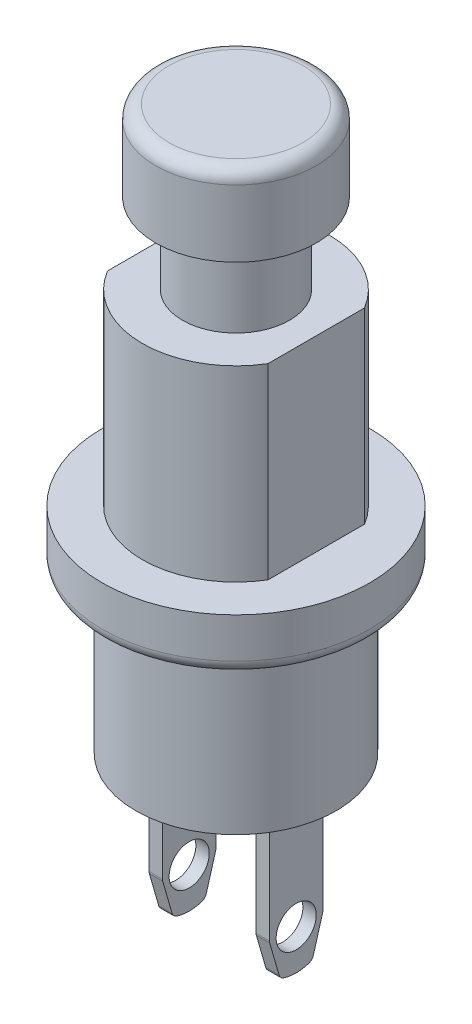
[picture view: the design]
ISO-10303-21;
HEADER;
FILE_DESCRIPTION(('STEP AP214'),'2;1');
FILE_NAME('part.step','',(''),(''),'','','');
FILE_SCHEMA(('AUTOMOTIVE_DESIGN { 1 0 10303 214 1 1 1 1 }'));
ENDSEC;
DATA;
#1=APPLICATION_CONTEXT('core data for automotive mechanical design processes');
#2=APPLICATION_PROTOCOL_DEFINITION('international standard','automotive_design',2000,#1);
#3=PRODUCT_CONTEXT('',#1,'mechanical');
#4=PRODUCT('Part','Part','',(#3));
#5=PRODUCT_RELATED_PRODUCT_CATEGORY('part','',(#4));
#6=PRODUCT_DEFINITION_FORMATION('','',#4);
#7=PRODUCT_DEFINITION_CONTEXT('part definition',#1,'design');
#8=PRODUCT_DEFINITION('design','',#6,#7);
#9=PRODUCT_DEFINITION_SHAPE('','',#8);
#10=(LENGTH_UNIT() NAMED_UNIT(*) SI_UNIT(.MILLI.,.METRE.));
#11=(NAMED_UNIT(*) PLANE_ANGLE_UNIT() SI_UNIT($,.RADIAN.));
#12=(NAMED_UNIT(*) SI_UNIT($,.STERADIAN.) SOLID_ANGLE_UNIT());
#13=UNCERTAINTY_MEASURE_WITH_UNIT(LENGTH_MEASURE(1.E-05),#10,'distance_accuracy_value','');
#14=(GEOMETRIC_REPRESENTATION_CONTEXT(3) GLOBAL_UNCERTAINTY_ASSIGNED_CONTEXT((#13)) GLOBAL_UNIT_ASSIGNED_CONTEXT((#10,
#11,#12)) REPRESENTATION_CONTEXT('',''));
#15=CARTESIAN_POINT('',(0.,0.,0.));
#16=DIRECTION('',(0.,0.,1.));
#17=DIRECTION('',(1.,0.,0.));
#18=AXIS2_PLACEMENT_3D('',#15,#16,#17);
#19=CARTESIAN_POINT('',(0.,15.,0.));
#20=DIRECTION('',(0.,1.,0.));
#21=DIRECTION('',(0.,0.,1.));
#22=AXIS2_PLACEMENT_3D('',#19,#20,#21);
#23=PLANE('',#22);
#24=CARTESIAN_POINT('',(0.,15.,0.));
#25=DIRECTION('',(0.,1.,0.));
#26=DIRECTION('',(0.,0.,1.));
#27=AXIS2_PLACEMENT_3D('',#24,#25,#26);
#28=CIRCLE('',#27,3.5);
#29=CARTESIAN_POINT('',(3.,15.,-1.802775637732));
#30=VERTEX_POINT('',#29);
#31=CARTESIAN_POINT('',(-3.,15.,-1.802775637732));
#32=VERTEX_POINT('',#31);
#33=EDGE_CURVE('E380',#30,#32,#28,.T.);
#34=ORIENTED_EDGE('',*,*,#33,.T.);
#35=DIRECTION('',(0.,0.,1.));
#36=VECTOR('',#35,1.);
#37=CARTESIAN_POINT('',(-3.,15.,1.802775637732));
#38=LINE('',#37,#36);
#39=CARTESIAN_POINT('',(-3.,15.,1.802775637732));
#40=VERTEX_POINT('',#39);
#41=EDGE_CURVE('E354',#32,#40,#38,.T.);
#42=ORIENTED_EDGE('',*,*,#41,.T.);
#43=CARTESIAN_POINT('',(0.,15.,0.));
#44=DIRECTION('',(0.,1.,0.));
#45=DIRECTION('',(0.,0.,1.));
#46=AXIS2_PLACEMENT_3D('',#43,#44,#45);
#47=CIRCLE('',#46,3.5);
#48=CARTESIAN_POINT('',(3.,15.,1.80277563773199));
#49=VERTEX_POINT('',#48);
#50=EDGE_CURVE('E383',#40,#49,#47,.T.);
#51=ORIENTED_EDGE('',*,*,#50,.T.);
#52=DIRECTION('',(0.,0.,-1.));
#53=VECTOR('',#52,1.);
#54=CARTESIAN_POINT('',(3.,15.,1.802775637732));
#55=LINE('',#54,#53);
#56=EDGE_CURVE('E385',#49,#30,#55,.T.);
#57=ORIENTED_EDGE('',*,*,#56,.T.);
#58=EDGE_LOOP('',(#34,#42,#51,#57));
#59=FACE_BOUND('',#58,.T.);
#60=CARTESIAN_POINT('',(0.,15.,0.));
#61=DIRECTION('',(0.,1.,0.));
#62=DIRECTION('',(0.,0.,1.));
#63=AXIS2_PLACEMENT_3D('',#60,#61,#62);
#64=CIRCLE('',#63,2.);
#65=CARTESIAN_POINT('',(0.,15.,2.));
#66=VERTEX_POINT('',#65);
#67=EDGE_CURVE('E1044',#66,#66,#64,.T.);
#68=ORIENTED_EDGE('',*,*,#67,.F.);
#69=EDGE_LOOP('',(#68));
#70=FACE_BOUND('',#69,.T.);
#71=ADVANCED_FACE('F136',(#59,#70),#23,.T.);
#72=CARTESIAN_POINT('',(0.,8.,0.));
#73=DIRECTION('',(0.,1.,0.));
#74=DIRECTION('',(0.,0.,1.));
#75=AXIS2_PLACEMENT_3D('',#72,#73,#74);
#76=PLANE('',#75);
#77=CARTESIAN_POINT('',(0.,8.,0.));
#78=DIRECTION('',(0.,1.,0.));
#79=DIRECTION('',(0.,0.,1.));
#80=AXIS2_PLACEMENT_3D('',#77,#78,#79);
#81=CIRCLE('',#80,5.);
#82=CARTESIAN_POINT('',(0.,8.,5.));
#83=VERTEX_POINT('',#82);
#84=EDGE_CURVE('E358',#83,#83,#81,.T.);
#85=ORIENTED_EDGE('',*,*,#84,.T.);
#86=EDGE_LOOP('',(#85));
#87=FACE_BOUND('',#86,.T.);
#88=DIRECTION('',(0.,0.,1.));
#89=VECTOR('',#88,1.);
#90=CARTESIAN_POINT('',(-3.,8.,1.802775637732));
#91=LINE('',#90,#89);
#92=CARTESIAN_POINT('',(-3.,8.,-1.802775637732));
#93=VERTEX_POINT('',#92);
#94=CARTESIAN_POINT('',(-3.,8.,1.802775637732));
#95=VERTEX_POINT('',#94);
#96=EDGE_CURVE('E352',#93,#95,#91,.T.);
#97=ORIENTED_EDGE('',*,*,#96,.F.);
#98=CARTESIAN_POINT('',(0.,8.,0.));
#99=DIRECTION('',(0.,1.,0.));
#100=DIRECTION('',(0.,0.,1.));
#101=AXIS2_PLACEMENT_3D('',#98,#99,#100);
#102=CIRCLE('',#101,3.5);
#103=CARTESIAN_POINT('',(3.,8.,-1.802775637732));
#104=VERTEX_POINT('',#103);
#105=EDGE_CURVE('E363',#104,#93,#102,.T.);
#106=ORIENTED_EDGE('',*,*,#105,.F.);
#107=DIRECTION('',(0.,0.,-1.));
#108=VECTOR('',#107,1.);
#109=CARTESIAN_POINT('',(3.,8.,1.802775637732));
#110=LINE('',#109,#108);
#111=CARTESIAN_POINT('',(3.,8.,1.80277563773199));
#112=VERTEX_POINT('',#111);
#113=EDGE_CURVE('E375',#112,#104,#110,.T.);
#114=ORIENTED_EDGE('',*,*,#113,.F.);
#115=CARTESIAN_POINT('',(0.,8.,0.));
#116=DIRECTION('',(0.,1.,0.));
#117=DIRECTION('',(0.,0.,1.));
#118=AXIS2_PLACEMENT_3D('',#115,#116,#117);
#119=CIRCLE('',#118,3.5);
#120=EDGE_CURVE('E373',#95,#112,#119,.T.);
#121=ORIENTED_EDGE('',*,*,#120,.F.);
#122=EDGE_LOOP('',(#97,#106,#114,#121));
#123=FACE_BOUND('',#122,.T.);
#124=ADVANCED_FACE('F372',(#87,#123),#76,.T.);
#125=CARTESIAN_POINT('',(1.75,-6.,1.5));
#126=DIRECTION('',(1.,0.,0.));
#127=DIRECTION('',(0.,0.,-1.));
#128=AXIS2_PLACEMENT_3D('',#125,#126,#127);
#129=PLANE('',#128);
#130=DIRECTION('',(0.,1.,0.));
#131=VECTOR('',#130,1.);
#132=CARTESIAN_POINT('',(1.75,-6.,1.));
#133=LINE('',#132,#131);
#134=CARTESIAN_POINT('',(1.75,-4.46468512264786,1.));
#135=VERTEX_POINT('',#134);
#136=CARTESIAN_POINT('',(1.75,-0.5,1.));
#137=VERTEX_POINT('',#136);
#138=EDGE_CURVE('E449',#135,#137,#133,.T.);
#139=ORIENTED_EDGE('',*,*,#138,.T.);
#140=DIRECTION('',(0.,0.,1.));
#141=VECTOR('',#140,1.);
#142=CARTESIAN_POINT('',(1.75,-0.5,1.5));
#143=LINE('',#142,#141);
#144=CARTESIAN_POINT('',(1.75,-0.5,1.5));
#145=VERTEX_POINT('',#144);
#146=EDGE_CURVE('E431',#137,#145,#143,.T.);
#147=ORIENTED_EDGE('',*,*,#146,.T.);
#148=DIRECTION('',(0.,1.,0.));
#149=VECTOR('',#148,1.);
#150=CARTESIAN_POINT('',(1.75,-6.,1.5));
#151=LINE('',#150,#149);
#152=CARTESIAN_POINT('',(1.75,0.,1.5));
#153=VERTEX_POINT('',#152);
#154=EDGE_CURVE('E568',#145,#153,#151,.T.);
#155=ORIENTED_EDGE('',*,*,#154,.T.);
#156=DIRECTION('',(0.,0.,-1.));
#157=VECTOR('',#156,1.);
#158=CARTESIAN_POINT('',(1.75,0.,1.5));
#159=LINE('',#158,#157);
#160=CARTESIAN_POINT('',(1.75,0.,-1.5));
#161=VERTEX_POINT('',#160);
#162=EDGE_CURVE('E553',#153,#161,#159,.T.);
#163=ORIENTED_EDGE('',*,*,#162,.T.);
#164=DIRECTION('',(0.,1.,0.));
#165=VECTOR('',#164,1.);
#166=CARTESIAN_POINT('',(1.75,-6.,-1.5));
#167=LINE('',#166,#165);
#168=CARTESIAN_POINT('',(1.75,-0.5,-1.5));
#169=VERTEX_POINT('',#168);
#170=EDGE_CURVE('E566',#169,#161,#167,.T.);
#171=ORIENTED_EDGE('',*,*,#170,.F.);
#172=DIRECTION('',(0.,0.,-1.));
#173=VECTOR('',#172,1.);
#174=CARTESIAN_POINT('',(1.75,-0.5,1.5));
#175=LINE('',#174,#173);
#176=CARTESIAN_POINT('',(1.75,-0.5,-1.));
#177=VERTEX_POINT('',#176);
#178=EDGE_CURVE('E530',#177,#169,#175,.T.);
#179=ORIENTED_EDGE('',*,*,#178,.F.);
#180=DIRECTION('',(0.,1.,0.));
#181=VECTOR('',#180,1.);
#182=CARTESIAN_POINT('',(1.75,-6.,-1.));
#183=LINE('',#182,#181);
#184=CARTESIAN_POINT('',(1.75,-4.46468512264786,-1.));
#185=VERTEX_POINT('',#184);
#186=EDGE_CURVE('E526',#185,#177,#183,.T.);
#187=ORIENTED_EDGE('',*,*,#186,.F.);
#188=CARTESIAN_POINT('',(1.75,-4.46468512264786,-0.75));
#189=DIRECTION('',(1.,0.,0.));
#190=DIRECTION('',(0.,0.,-1.));
#191=AXIS2_PLACEMENT_3D('',#188,#189,#190);
#192=CIRCLE('',#191,0.25);
#193=CARTESIAN_POINT('',(1.75,-4.53393308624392,-0.990218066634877));
#194=VERTEX_POINT('',#193);
#195=EDGE_CURVE('E521',#185,#194,#192,.F.);
#196=ORIENTED_EDGE('',*,*,#195,.T.);
#197=DIRECTION('',(0.,0.960872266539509,-0.276991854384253));
#198=VECTOR('',#197,1.);
#199=CARTESIAN_POINT('',(1.75,-6.55029774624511,-0.408958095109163));
#200=LINE('',#199,#198);
#201=CARTESIAN_POINT('',(1.75,-5.75410647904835,-0.638477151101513));
#202=VERTEX_POINT('',#201);
#203=EDGE_CURVE('E516',#202,#194,#200,.T.);
#204=ORIENTED_EDGE('',*,*,#203,.F.);
#205=CARTESIAN_POINT('',(1.75,-5.68485851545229,-0.398259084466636));
#206=DIRECTION('',(1.,0.,0.));
#207=DIRECTION('',(0.,0.,-1.));
#208=AXIS2_PLACEMENT_3D('',#205,#206,#207);
#209=CIRCLE('',#208,0.25);
#210=CARTESIAN_POINT('',(1.75,-5.92183021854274,-0.477910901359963));
#211=VERTEX_POINT('',#210);
#212=EDGE_CURVE('E511',#202,#211,#209,.F.);
#213=ORIENTED_EDGE('',*,*,#212,.T.);
#214=CARTESIAN_POINT('',(1.75,-4.5,0.));
#215=DIRECTION('',(1.,0.,0.));
#216=DIRECTION('',(0.,0.,-1.));
#217=AXIS2_PLACEMENT_3D('',#214,#215,#216);
#218=CIRCLE('',#217,1.5);
#219=CARTESIAN_POINT('',(1.75,-5.92183021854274,0.477910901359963));
#220=VERTEX_POINT('',#219);
#221=EDGE_CURVE('E506',#220,#211,#218,.T.);
#222=ORIENTED_EDGE('',*,*,#221,.F.);
#223=CARTESIAN_POINT('',(1.75,-5.68485851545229,0.398259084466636));
#224=DIRECTION('',(1.,0.,0.));
#225=DIRECTION('',(0.,0.,-1.));
#226=AXIS2_PLACEMENT_3D('',#223,#224,#225);
#227=CIRCLE('',#226,0.25);
#228=CARTESIAN_POINT('',(1.75,-5.75410647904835,0.638477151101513));
#229=VERTEX_POINT('',#228);
#230=EDGE_CURVE('E443',#220,#229,#227,.F.);
#231=ORIENTED_EDGE('',*,*,#230,.T.);
#232=DIRECTION('',(0.,0.960872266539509,0.276991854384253));
#233=VECTOR('',#232,1.);
#234=CARTESIAN_POINT('',(1.75,-5.75183637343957,0.639131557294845));
#235=LINE('',#234,#233);
#236=CARTESIAN_POINT('',(1.75,-4.53393308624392,0.990218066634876));
#237=VERTEX_POINT('',#236);
#238=EDGE_CURVE('E437',#229,#237,#235,.T.);
#239=ORIENTED_EDGE('',*,*,#238,.T.);
#240=CARTESIAN_POINT('',(1.75,-4.46468512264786,0.75));
#241=DIRECTION('',(1.,0.,0.));
#242=DIRECTION('',(0.,0.,-1.));
#243=AXIS2_PLACEMENT_3D('',#240,#241,#242);
#244=CIRCLE('',#243,0.25);
#245=EDGE_CURVE('E454',#135,#237,#244,.T.);
#246=ORIENTED_EDGE('',*,*,#245,.F.);
#247=EDGE_LOOP('',(#139,#147,#155,#163,#171,#179,#187,#196,#204,#213,#222,#231,#239,#246));
#248=FACE_BOUND('',#247,.T.);
#249=CARTESIAN_POINT('',(1.75,-4.5,0.));
#250=DIRECTION('',(1.,0.,0.));
#251=DIRECTION('',(0.,0.,-1.));
#252=AXIS2_PLACEMENT_3D('',#249,#250,#251);
#253=CIRCLE('',#252,0.75);
#254=CARTESIAN_POINT('',(1.75,-4.5,-0.75));
#255=VERTEX_POINT('',#254);
#256=EDGE_CURVE('E463',#255,#255,#253,.T.);
#257=ORIENTED_EDGE('',*,*,#256,.T.);
#258=EDGE_LOOP('',(#257));
#259=FACE_BOUND('',#258,.T.);
#260=ADVANCED_FACE('F631',(#248,#259),#129,.F.);
#261=CARTESIAN_POINT('',(1.75,-6.,-1.5));
#262=DIRECTION('',(0.,0.,1.));
#263=DIRECTION('',(1.,0.,0.));
#264=AXIS2_PLACEMENT_3D('',#261,#262,#263);
#265=PLANE('',#264);
#266=DIRECTION('',(-1.,0.,0.));
#267=VECTOR('',#266,1.);
#268=CARTESIAN_POINT('',(3.75,-0.5,-1.5));
#269=LINE('',#268,#267);
#270=CARTESIAN_POINT('',(2.25,-0.5,-1.5));
#271=VERTEX_POINT('',#270);
#272=EDGE_CURVE('E487',#271,#169,#269,.T.);
#273=ORIENTED_EDGE('',*,*,#272,.T.);
#274=ORIENTED_EDGE('',*,*,#170,.T.);
#275=DIRECTION('',(1.,0.,0.));
#276=VECTOR('',#275,1.);
#277=CARTESIAN_POINT('',(1.75,0.,-1.5));
#278=LINE('',#277,#276);
#279=CARTESIAN_POINT('',(2.25,0.,-1.5));
#280=VERTEX_POINT('',#279);
#281=EDGE_CURVE('E556',#161,#280,#278,.T.);
#282=ORIENTED_EDGE('',*,*,#281,.T.);
#283=DIRECTION('',(0.,1.,0.));
#284=VECTOR('',#283,1.);
#285=CARTESIAN_POINT('',(2.25,-6.,-1.5));
#286=LINE('',#285,#284);
#287=EDGE_CURVE('E564',#271,#280,#286,.T.);
#288=ORIENTED_EDGE('',*,*,#287,.F.);
#289=EDGE_LOOP('',(#273,#274,#282,#288));
#290=FACE_BOUND('',#289,.T.);
#291=ADVANCED_FACE('F742',(#290),#265,.F.);
#292=CARTESIAN_POINT('',(2.25,-6.,1.5));
#293=DIRECTION('',(-1.,0.,0.));
#294=DIRECTION('',(0.,0.,1.));
#295=AXIS2_PLACEMENT_3D('',#292,#293,#294);
#296=PLANE('',#295);
#297=CARTESIAN_POINT('',(2.25,-4.5,0.));
#298=DIRECTION('',(-1.,0.,0.));
#299=DIRECTION('',(0.,0.,1.));
#300=AXIS2_PLACEMENT_3D('',#297,#298,#299);
#301=CIRCLE('',#300,0.75);
#302=CARTESIAN_POINT('',(2.25,-4.5,0.75));
#303=VERTEX_POINT('',#302);
#304=EDGE_CURVE('E460',#303,#303,#301,.T.);
#305=ORIENTED_EDGE('',*,*,#304,.T.);
#306=EDGE_LOOP('',(#305));
#307=FACE_BOUND('',#306,.T.);
#308=DIRECTION('',(0.,1.,0.));
#309=VECTOR('',#308,1.);
#310=CARTESIAN_POINT('',(2.25,-6.,1.5));
#311=LINE('',#310,#309);
#312=CARTESIAN_POINT('',(2.25,-0.5,1.5));
#313=VERTEX_POINT('',#312);
#314=CARTESIAN_POINT('',(2.25,0.,1.5));
#315=VERTEX_POINT('',#314);
#316=EDGE_CURVE('E562',#313,#315,#311,.T.);
#317=ORIENTED_EDGE('',*,*,#316,.F.);
#318=DIRECTION('',(0.,0.,-1.));
#319=VECTOR('',#318,1.);
#320=CARTESIAN_POINT('',(2.25,-0.5,1.5));
#321=LINE('',#320,#319);
#322=CARTESIAN_POINT('',(2.25,-0.5,1.));
#323=VERTEX_POINT('',#322);
#324=EDGE_CURVE('E428',#313,#323,#321,.T.);
#325=ORIENTED_EDGE('',*,*,#324,.T.);
#326=DIRECTION('',(0.,-1.,0.));
#327=VECTOR('',#326,1.);
#328=CARTESIAN_POINT('',(2.25,-6.,1.));
#329=LINE('',#328,#327);
#330=CARTESIAN_POINT('',(2.25,-4.46468512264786,1.));
#331=VERTEX_POINT('',#330);
#332=EDGE_CURVE('E446',#323,#331,#329,.T.);
#333=ORIENTED_EDGE('',*,*,#332,.T.);
#334=CARTESIAN_POINT('',(2.25,-4.46468512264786,0.75));
#335=DIRECTION('',(-1.,0.,0.));
#336=DIRECTION('',(0.,0.,1.));
#337=AXIS2_PLACEMENT_3D('',#334,#335,#336);
#338=CIRCLE('',#337,0.25);
#339=CARTESIAN_POINT('',(2.25,-4.53393308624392,0.990218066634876));
#340=VERTEX_POINT('',#339);
#341=EDGE_CURVE('E452',#340,#331,#338,.T.);
#342=ORIENTED_EDGE('',*,*,#341,.F.);
#343=DIRECTION('',(0.,-0.960872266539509,-0.276991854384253));
#344=VECTOR('',#343,1.);
#345=CARTESIAN_POINT('',(2.25,-5.75183637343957,0.639131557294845));
#346=LINE('',#345,#344);
#347=CARTESIAN_POINT('',(2.25,-5.75410647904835,0.638477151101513));
#348=VERTEX_POINT('',#347);
#349=EDGE_CURVE('E434',#340,#348,#346,.T.);
#350=ORIENTED_EDGE('',*,*,#349,.T.);
#351=CARTESIAN_POINT('',(2.25,-5.68485851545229,0.398259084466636));
#352=DIRECTION('',(-1.,0.,0.));
#353=DIRECTION('',(0.,0.,1.));
#354=AXIS2_PLACEMENT_3D('',#351,#352,#353);
#355=CIRCLE('',#354,0.25);
#356=CARTESIAN_POINT('',(2.25,-5.92183021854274,0.477910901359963));
#357=VERTEX_POINT('',#356);
#358=EDGE_CURVE('E440',#348,#357,#355,.F.);
#359=ORIENTED_EDGE('',*,*,#358,.T.);
#360=CARTESIAN_POINT('',(2.25,-4.5,0.));
#361=DIRECTION('',(-1.,0.,0.));
#362=DIRECTION('',(0.,0.,1.));
#363=AXIS2_PLACEMENT_3D('',#360,#361,#362);
#364=CIRCLE('',#363,1.5);
#365=CARTESIAN_POINT('',(2.25,-5.92183021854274,-0.477910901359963));
#366=VERTEX_POINT('',#365);
#367=EDGE_CURVE('E504',#366,#357,#364,.T.);
#368=ORIENTED_EDGE('',*,*,#367,.F.);
#369=CARTESIAN_POINT('',(2.25,-5.68485851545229,-0.398259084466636));
#370=DIRECTION('',(-1.,0.,0.));
#371=DIRECTION('',(0.,0.,1.));
#372=AXIS2_PLACEMENT_3D('',#369,#370,#371);
#373=CIRCLE('',#372,0.25);
#374=CARTESIAN_POINT('',(2.25,-5.75410647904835,-0.638477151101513));
#375=VERTEX_POINT('',#374);
#376=EDGE_CURVE('E508',#366,#375,#373,.F.);
#377=ORIENTED_EDGE('',*,*,#376,.T.);
#378=DIRECTION('',(0.,-0.960872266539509,0.276991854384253));
#379=VECTOR('',#378,1.);
#380=CARTESIAN_POINT('',(2.25,-6.55029774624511,-0.408958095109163));
#381=LINE('',#380,#379);
#382=CARTESIAN_POINT('',(2.25,-4.53393308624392,-0.990218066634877));
#383=VERTEX_POINT('',#382);
#384=EDGE_CURVE('E514',#383,#375,#381,.T.);
#385=ORIENTED_EDGE('',*,*,#384,.F.);
#386=CARTESIAN_POINT('',(2.25,-4.46468512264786,-0.75));
#387=DIRECTION('',(-1.,0.,0.));
#388=DIRECTION('',(0.,0.,1.));
#389=AXIS2_PLACEMENT_3D('',#386,#387,#388);
#390=CIRCLE('',#389,0.25);
#391=CARTESIAN_POINT('',(2.25,-4.46468512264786,-1.));
#392=VERTEX_POINT('',#391);
#393=EDGE_CURVE('E518',#383,#392,#390,.F.);
#394=ORIENTED_EDGE('',*,*,#393,.T.);
#395=DIRECTION('',(0.,-1.,0.));
#396=VECTOR('',#395,1.);
#397=CARTESIAN_POINT('',(2.25,-6.,-1.));
#398=LINE('',#397,#396);
#399=CARTESIAN_POINT('',(2.25,-0.5,-1.));
#400=VERTEX_POINT('',#399);
#401=EDGE_CURVE('E524',#400,#392,#398,.T.);
#402=ORIENTED_EDGE('',*,*,#401,.F.);
#403=DIRECTION('',(0.,0.,1.));
#404=VECTOR('',#403,1.);
#405=CARTESIAN_POINT('',(2.25,-0.5,1.5));
#406=LINE('',#405,#404);
#407=EDGE_CURVE('E528',#271,#400,#406,.T.);
#408=ORIENTED_EDGE('',*,*,#407,.F.);
#409=ORIENTED_EDGE('',*,*,#287,.T.);
#410=DIRECTION('',(0.,0.,1.));
#411=VECTOR('',#410,1.);
#412=CARTESIAN_POINT('',(2.25,0.,1.5));
#413=LINE('',#412,#411);
#414=EDGE_CURVE('E559',#280,#315,#413,.T.);
#415=ORIENTED_EDGE('',*,*,#414,.T.);
#416=EDGE_LOOP('',(#317,#325,#333,#342,#350,#359,#368,#377,#385,#394,#402,#408,#409,#415));
#417=FACE_BOUND('',#416,.T.);
#418=ADVANCED_FACE('F734',(#307,#417),#296,.F.);
#419=CARTESIAN_POINT('',(-2.25,-6.,1.5));
#420=DIRECTION('',(1.,0.,0.));
#421=DIRECTION('',(0.,0.,-1.));
#422=AXIS2_PLACEMENT_3D('',#419,#420,#421);
#423=PLANE('',#422);
#424=DIRECTION('',(0.,-1.,0.));
#425=VECTOR('',#424,1.);
#426=CARTESIAN_POINT('',(-2.25,-10.7684253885,1.));
#427=LINE('',#426,#425);
#428=CARTESIAN_POINT('',(-2.25,-0.5,1.));
#429=VERTEX_POINT('',#428);
#430=CARTESIAN_POINT('',(-2.25,-4.46468512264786,1.));
#431=VERTEX_POINT('',#430);
#432=EDGE_CURVE('E411',#429,#431,#427,.T.);
#433=ORIENTED_EDGE('',*,*,#432,.F.);
#434=DIRECTION('',(0.,0.,-1.));
#435=VECTOR('',#434,1.);
#436=CARTESIAN_POINT('',(-2.25,-0.5,0.));
#437=LINE('',#436,#435);
#438=CARTESIAN_POINT('',(-2.25,-0.5,1.5));
#439=VERTEX_POINT('',#438);
#440=EDGE_CURVE('E415',#439,#429,#437,.T.);
#441=ORIENTED_EDGE('',*,*,#440,.F.);
#442=DIRECTION('',(0.,1.,0.));
#443=VECTOR('',#442,1.);
#444=CARTESIAN_POINT('',(-2.25,-6.,1.5));
#445=LINE('',#444,#443);
#446=CARTESIAN_POINT('',(-2.25,0.,1.5));
#447=VERTEX_POINT('',#446);
#448=EDGE_CURVE('E159',#439,#447,#445,.T.);
#449=ORIENTED_EDGE('',*,*,#448,.T.);
#450=DIRECTION('',(0.,0.,-1.));
#451=VECTOR('',#450,1.);
#452=CARTESIAN_POINT('',(-2.25,0.,1.5));
#453=LINE('',#452,#451);
#454=CARTESIAN_POINT('',(-2.25,0.,-1.5));
#455=VERTEX_POINT('',#454);
#456=EDGE_CURVE('E535',#447,#455,#453,.T.);
#457=ORIENTED_EDGE('',*,*,#456,.T.);
#458=DIRECTION('',(0.,1.,0.));
#459=VECTOR('',#458,1.);
#460=CARTESIAN_POINT('',(-2.25,-6.,-1.5));
#461=LINE('',#460,#459);
#462=CARTESIAN_POINT('',(-2.25,-0.5,-1.5));
#463=VERTEX_POINT('',#462);
#464=EDGE_CURVE('E547',#463,#455,#461,.T.);
#465=ORIENTED_EDGE('',*,*,#464,.F.);
#466=DIRECTION('',(0.,0.,1.));
#467=VECTOR('',#466,1.);
#468=CARTESIAN_POINT('',(-2.25,-0.5,0.));
#469=LINE('',#468,#467);
#470=CARTESIAN_POINT('',(-2.25,-0.5,-1.));
#471=VERTEX_POINT('',#470);
#472=EDGE_CURVE('E480',#463,#471,#469,.T.);
#473=ORIENTED_EDGE('',*,*,#472,.T.);
#474=DIRECTION('',(0.,-1.,0.));
#475=VECTOR('',#474,1.);
#476=CARTESIAN_POINT('',(-2.25,-10.7684253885,-1.));
#477=LINE('',#476,#475);
#478=CARTESIAN_POINT('',(-2.25,-4.46468512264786,-1.));
#479=VERTEX_POINT('',#478);
#480=EDGE_CURVE('E477',#471,#479,#477,.T.);
#481=ORIENTED_EDGE('',*,*,#480,.T.);
#482=CARTESIAN_POINT('',(-2.25,-4.46468512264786,-0.75));
#483=DIRECTION('',(-1.,0.,0.));
#484=DIRECTION('',(0.,0.,1.));
#485=AXIS2_PLACEMENT_3D('',#482,#483,#484);
#486=CIRCLE('',#485,0.25);
#487=CARTESIAN_POINT('',(-2.25,-4.53393308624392,-0.990218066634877));
#488=VERTEX_POINT('',#487);
#489=EDGE_CURVE('E474',#488,#479,#486,.F.);
#490=ORIENTED_EDGE('',*,*,#489,.F.);
#491=DIRECTION('',(0.,-0.960872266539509,0.276991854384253));
#492=VECTOR('',#491,1.);
#493=CARTESIAN_POINT('',(-2.25,-10.5536374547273,0.745089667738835));
#494=LINE('',#493,#492);
#495=CARTESIAN_POINT('',(-2.25,-5.75410647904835,-0.638477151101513));
#496=VERTEX_POINT('',#495);
#497=EDGE_CURVE('E471',#488,#496,#494,.T.);
#498=ORIENTED_EDGE('',*,*,#497,.T.);
#499=CARTESIAN_POINT('',(-2.25,-5.68485851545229,-0.398259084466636));
#500=DIRECTION('',(-1.,0.,0.));
#501=DIRECTION('',(0.,0.,1.));
#502=AXIS2_PLACEMENT_3D('',#499,#500,#501);
#503=CIRCLE('',#502,0.25);
#504=CARTESIAN_POINT('',(-2.25,-5.92183021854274,-0.477910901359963));
#505=VERTEX_POINT('',#504);
#506=EDGE_CURVE('E468',#505,#496,#503,.F.);
#507=ORIENTED_EDGE('',*,*,#506,.F.);
#508=CARTESIAN_POINT('',(-2.25,-4.5,0.));
#509=DIRECTION('',(-1.,0.,0.));
#510=DIRECTION('',(0.,0.,1.));
#511=AXIS2_PLACEMENT_3D('',#508,#509,#510);
#512=CIRCLE('',#511,1.5);
#513=CARTESIAN_POINT('',(-2.25,-5.92183021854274,0.477910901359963));
#514=VERTEX_POINT('',#513);
#515=EDGE_CURVE('E466',#505,#514,#512,.T.);
#516=ORIENTED_EDGE('',*,*,#515,.T.);
#517=CARTESIAN_POINT('',(-2.25,-5.68485851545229,0.398259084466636));
#518=DIRECTION('',(-1.,0.,0.));
#519=DIRECTION('',(0.,0.,1.));
#520=AXIS2_PLACEMENT_3D('',#517,#518,#519);
#521=CIRCLE('',#520,0.25);
#522=CARTESIAN_POINT('',(-2.25,-5.75410647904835,0.638477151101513));
#523=VERTEX_POINT('',#522);
#524=EDGE_CURVE('E418',#523,#514,#521,.F.);
#525=ORIENTED_EDGE('',*,*,#524,.F.);
#526=DIRECTION('',(0.,-0.960872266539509,-0.276991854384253));
#527=VECTOR('',#526,1.);
#528=CARTESIAN_POINT('',(-2.25,-10.5536374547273,-0.745089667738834));
#529=LINE('',#528,#527);
#530=CARTESIAN_POINT('',(-2.25,-4.53393308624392,0.990218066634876));
#531=VERTEX_POINT('',#530);
#532=EDGE_CURVE('E421',#531,#523,#529,.T.);
#533=ORIENTED_EDGE('',*,*,#532,.F.);
#534=CARTESIAN_POINT('',(-2.25,-4.46468512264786,0.75));
#535=DIRECTION('',(-1.,0.,0.));
#536=DIRECTION('',(0.,0.,1.));
#537=AXIS2_PLACEMENT_3D('',#534,#535,#536);
#538=CIRCLE('',#537,0.25);
#539=EDGE_CURVE('E392',#531,#431,#538,.T.);
#540=ORIENTED_EDGE('',*,*,#539,.T.);
#541=EDGE_LOOP('',(#433,#441,#449,#457,#465,#473,#481,#490,#498,#507,#516,#525,#533,#540));
#542=FACE_BOUND('',#541,.T.);
#543=CARTESIAN_POINT('',(-2.25,-4.5,0.));
#544=DIRECTION('',(-1.,0.,0.));
#545=DIRECTION('',(0.,0.,1.));
#546=AXIS2_PLACEMENT_3D('',#543,#544,#545);
#547=CIRCLE('',#546,0.75);
#548=CARTESIAN_POINT('',(-2.25,-4.5,0.75));
#549=VERTEX_POINT('',#548);
#550=EDGE_CURVE('E456',#549,#549,#547,.T.);
#551=ORIENTED_EDGE('',*,*,#550,.F.);
#552=EDGE_LOOP('',(#551));
#553=FACE_BOUND('',#552,.T.);
#554=ADVANCED_FACE('F730',(#542,#553),#423,.F.);
#555=CARTESIAN_POINT('',(-2.25,-6.,-1.5));
#556=DIRECTION('',(0.,0.,1.));
#557=DIRECTION('',(1.,0.,0.));
#558=AXIS2_PLACEMENT_3D('',#555,#556,#557);
#559=PLANE('',#558);
#560=CARTESIAN_POINT('',(-1.75,-0.5,-1.5));
#561=VERTEX_POINT('',#560);
#562=EDGE_CURVE('E484',#561,#463,#269,.T.);
#563=ORIENTED_EDGE('',*,*,#562,.T.);
#564=ORIENTED_EDGE('',*,*,#464,.T.);
#565=DIRECTION('',(1.,0.,0.));
#566=VECTOR('',#565,1.);
#567=CARTESIAN_POINT('',(-2.25,0.,-1.5));
#568=LINE('',#567,#566);
#569=CARTESIAN_POINT('',(-1.75,0.,-1.5));
#570=VERTEX_POINT('',#569);
#571=EDGE_CURVE('E537',#455,#570,#568,.T.);
#572=ORIENTED_EDGE('',*,*,#571,.T.);
#573=DIRECTION('',(0.,1.,0.));
#574=VECTOR('',#573,1.);
#575=CARTESIAN_POINT('',(-1.75,-6.,-1.5));
#576=LINE('',#575,#574);
#577=EDGE_CURVE('E545',#561,#570,#576,.T.);
#578=ORIENTED_EDGE('',*,*,#577,.F.);
#579=EDGE_LOOP('',(#563,#564,#572,#578));
#580=FACE_BOUND('',#579,.T.);
#581=ADVANCED_FACE('F726',(#580),#559,.F.);
#582=CARTESIAN_POINT('',(-1.75,-6.,1.5));
#583=DIRECTION('',(-1.,0.,0.));
#584=DIRECTION('',(0.,0.,1.));
#585=AXIS2_PLACEMENT_3D('',#582,#583,#584);
#586=PLANE('',#585);
#587=CARTESIAN_POINT('',(-1.75,-4.5,0.));
#588=DIRECTION('',(-1.,0.,0.));
#589=DIRECTION('',(0.,0.,1.));
#590=AXIS2_PLACEMENT_3D('',#587,#588,#589);
#591=CIRCLE('',#590,0.75);
#592=CARTESIAN_POINT('',(-1.75,-4.5,0.75));
#593=VERTEX_POINT('',#592);
#594=EDGE_CURVE('E459',#593,#593,#591,.T.);
#595=ORIENTED_EDGE('',*,*,#594,.T.);
#596=EDGE_LOOP('',(#595));
#597=FACE_BOUND('',#596,.T.);
#598=DIRECTION('',(0.,1.,0.));
#599=VECTOR('',#598,1.);
#600=CARTESIAN_POINT('',(-1.75,-6.,1.5));
#601=LINE('',#600,#599);
#602=CARTESIAN_POINT('',(-1.75,-0.5,1.5));
#603=VERTEX_POINT('',#602);
#604=CARTESIAN_POINT('',(-1.75,0.,1.5));
#605=VERTEX_POINT('',#604);
#606=EDGE_CURVE('E543',#603,#605,#601,.T.);
#607=ORIENTED_EDGE('',*,*,#606,.F.);
#608=DIRECTION('',(0.,0.,-1.));
#609=VECTOR('',#608,1.);
#610=CARTESIAN_POINT('',(-1.75,-0.5,1.5));
#611=LINE('',#610,#609);
#612=CARTESIAN_POINT('',(-1.75,-0.5,1.));
#613=VERTEX_POINT('',#612);
#614=EDGE_CURVE('E414',#603,#613,#611,.T.);
#615=ORIENTED_EDGE('',*,*,#614,.T.);
#616=DIRECTION('',(0.,-1.,0.));
#617=VECTOR('',#616,1.);
#618=CARTESIAN_POINT('',(-1.75,-6.,1.));
#619=LINE('',#618,#617);
#620=CARTESIAN_POINT('',(-1.75,-4.46468512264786,1.));
#621=VERTEX_POINT('',#620);
#622=EDGE_CURVE('E601',#613,#621,#619,.T.);
#623=ORIENTED_EDGE('',*,*,#622,.T.);
#624=CARTESIAN_POINT('',(-1.75,-4.46468512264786,0.75));
#625=DIRECTION('',(-1.,0.,0.));
#626=DIRECTION('',(0.,0.,1.));
#627=AXIS2_PLACEMENT_3D('',#624,#625,#626);
#628=CIRCLE('',#627,0.25);
#629=CARTESIAN_POINT('',(-1.75,-4.53393308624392,0.990218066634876));
#630=VERTEX_POINT('',#629);
#631=EDGE_CURVE('E599',#630,#621,#628,.T.);
#632=ORIENTED_EDGE('',*,*,#631,.F.);
#633=DIRECTION('',(0.,-0.960872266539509,-0.276991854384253));
#634=VECTOR('',#633,1.);
#635=CARTESIAN_POINT('',(-1.75,-5.75183637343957,0.639131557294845));
#636=LINE('',#635,#634);
#637=CARTESIAN_POINT('',(-1.75,-5.75410647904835,0.638477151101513));
#638=VERTEX_POINT('',#637);
#639=EDGE_CURVE('E593',#630,#638,#636,.T.);
#640=ORIENTED_EDGE('',*,*,#639,.T.);
#641=CARTESIAN_POINT('',(-1.75,-5.68485851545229,0.398259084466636));
#642=DIRECTION('',(-1.,0.,0.));
#643=DIRECTION('',(0.,0.,1.));
#644=AXIS2_PLACEMENT_3D('',#641,#642,#643);
#645=CIRCLE('',#644,0.25);
#646=CARTESIAN_POINT('',(-1.75,-5.92183021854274,0.477910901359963));
#647=VERTEX_POINT('',#646);
#648=EDGE_CURVE('E596',#638,#647,#645,.F.);
#649=ORIENTED_EDGE('',*,*,#648,.T.);
#650=CARTESIAN_POINT('',(-1.75,-4.5,0.));
#651=DIRECTION('',(-1.,0.,0.));
#652=DIRECTION('',(0.,0.,1.));
#653=AXIS2_PLACEMENT_3D('',#650,#651,#652);
#654=CIRCLE('',#653,1.5);
#655=CARTESIAN_POINT('',(-1.75,-5.92183021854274,-0.477910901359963));
#656=VERTEX_POINT('',#655);
#657=EDGE_CURVE('E502',#656,#647,#654,.T.);
#658=ORIENTED_EDGE('',*,*,#657,.F.);
#659=CARTESIAN_POINT('',(-1.75,-5.68485851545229,-0.398259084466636));
#660=DIRECTION('',(-1.,0.,0.));
#661=DIRECTION('',(0.,0.,1.));
#662=AXIS2_PLACEMENT_3D('',#659,#660,#661);
#663=CIRCLE('',#662,0.25);
#664=CARTESIAN_POINT('',(-1.75,-5.75410647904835,-0.638477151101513));
#665=VERTEX_POINT('',#664);
#666=EDGE_CURVE('E576',#656,#665,#663,.F.);
#667=ORIENTED_EDGE('',*,*,#666,.T.);
#668=DIRECTION('',(0.,-0.960872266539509,0.276991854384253));
#669=VECTOR('',#668,1.);
#670=CARTESIAN_POINT('',(-1.75,-6.55029774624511,-0.408958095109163));
#671=LINE('',#670,#669);
#672=CARTESIAN_POINT('',(-1.75,-4.53393308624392,-0.990218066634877));
#673=VERTEX_POINT('',#672);
#674=EDGE_CURVE('E579',#673,#665,#671,.T.);
#675=ORIENTED_EDGE('',*,*,#674,.F.);
#676=CARTESIAN_POINT('',(-1.75,-4.46468512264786,-0.75));
#677=DIRECTION('',(-1.,0.,0.));
#678=DIRECTION('',(0.,0.,1.));
#679=AXIS2_PLACEMENT_3D('',#676,#677,#678);
#680=CIRCLE('',#679,0.25);
#681=CARTESIAN_POINT('',(-1.75,-4.46468512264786,-1.));
#682=VERTEX_POINT('',#681);
#683=EDGE_CURVE('E581',#673,#682,#680,.F.);
#684=ORIENTED_EDGE('',*,*,#683,.T.);
#685=DIRECTION('',(0.,-1.,0.));
#686=VECTOR('',#685,1.);
#687=CARTESIAN_POINT('',(-1.75,-6.,-1.));
#688=LINE('',#687,#686);
#689=CARTESIAN_POINT('',(-1.75,-0.5,-1.));
#690=VERTEX_POINT('',#689);
#691=EDGE_CURVE('E584',#690,#682,#688,.T.);
#692=ORIENTED_EDGE('',*,*,#691,.F.);
#693=DIRECTION('',(0.,0.,1.));
#694=VECTOR('',#693,1.);
#695=CARTESIAN_POINT('',(-1.75,-0.5,1.5));
#696=LINE('',#695,#694);
#697=EDGE_CURVE('E586',#561,#690,#696,.T.);
#698=ORIENTED_EDGE('',*,*,#697,.F.);
#699=ORIENTED_EDGE('',*,*,#577,.T.);
#700=DIRECTION('',(0.,0.,1.));
#701=VECTOR('',#700,1.);
#702=CARTESIAN_POINT('',(-1.75,0.,1.5));
#703=LINE('',#702,#701);
#704=EDGE_CURVE('E540',#570,#605,#703,.T.);
#705=ORIENTED_EDGE('',*,*,#704,.T.);
#706=EDGE_LOOP('',(#607,#615,#623,#632,#640,#649,#658,#667,#675,#684,#692,#698,#699,#705));
#707=FACE_BOUND('',#706,.T.);
#708=ADVANCED_FACE('F722',(#597,#707),#586,.F.);
#709=CARTESIAN_POINT('',(0.,0.,0.));
#710=DIRECTION('',(0.,1.,0.));
#711=DIRECTION('',(0.,0.,1.));
#712=AXIS2_PLACEMENT_3D('',#709,#710,#711);
#713=PLANE('',#712);
#714=DIRECTION('',(-1.,0.,0.));
#715=VECTOR('',#714,1.);
#716=CARTESIAN_POINT('',(1.75,0.,1.5));
#717=LINE('',#716,#715);
#718=EDGE_CURVE('E550',#315,#153,#717,.T.);
#719=ORIENTED_EDGE('',*,*,#718,.F.);
#720=ORIENTED_EDGE('',*,*,#414,.F.);
#721=ORIENTED_EDGE('',*,*,#281,.F.);
#722=ORIENTED_EDGE('',*,*,#162,.F.);
#723=EDGE_LOOP('',(#719,#720,#721,#722));
#724=FACE_BOUND('',#723,.T.);
#725=CARTESIAN_POINT('',(0.,0.,0.));
#726=DIRECTION('',(0.,1.,0.));
#727=DIRECTION('',(0.,0.,1.));
#728=AXIS2_PLACEMENT_3D('',#725,#726,#727);
#729=CIRCLE('',#728,3.75);
#730=CARTESIAN_POINT('',(0.,0.,3.75));
#731=VERTEX_POINT('',#730);
#732=EDGE_CURVE('E570',#731,#731,#729,.T.);
#733=ORIENTED_EDGE('',*,*,#732,.F.);
#734=EDGE_LOOP('',(#733));
#735=FACE_BOUND('',#734,.T.);
#736=DIRECTION('',(-1.,0.,0.));
#737=VECTOR('',#736,1.);
#738=CARTESIAN_POINT('',(-2.25,0.,1.5));
#739=LINE('',#738,#737);
#740=EDGE_CURVE('E532',#605,#447,#739,.T.);
#741=ORIENTED_EDGE('',*,*,#740,.F.);
#742=ORIENTED_EDGE('',*,*,#704,.F.);
#743=ORIENTED_EDGE('',*,*,#571,.F.);
#744=ORIENTED_EDGE('',*,*,#456,.F.);
#745=EDGE_LOOP('',(#741,#742,#743,#744));
#746=FACE_BOUND('',#745,.T.);
#747=ADVANCED_FACE('F725',(#724,#735,#746),#713,.F.);
#748=CARTESIAN_POINT('',(0.,6.,0.));
#749=DIRECTION('',(0.,-1.,0.));
#750=DIRECTION('',(0.,0.,-1.));
#751=AXIS2_PLACEMENT_3D('',#748,#749,#750);
#752=CYLINDRICAL_SURFACE('',#751,3.75);
#753=CARTESIAN_POINT('',(0.,6.,0.));
#754=DIRECTION('',(0.,1.,0.));
#755=DIRECTION('',(0.,0.,1.));
#756=AXIS2_PLACEMENT_3D('',#753,#754,#755);
#757=CIRCLE('',#756,3.75);
#758=CARTESIAN_POINT('',(0.,6.,3.75));
#759=VERTEX_POINT('',#758);
#760=EDGE_CURVE('E573',#759,#759,#757,.T.);
#761=ORIENTED_EDGE('',*,*,#760,.F.);
#762=EDGE_LOOP('',(#761));
#763=FACE_BOUND('',#762,.T.);
#764=ORIENTED_EDGE('',*,*,#732,.T.);
#765=EDGE_LOOP('',(#764));
#766=FACE_BOUND('',#765,.T.);
#767=ADVANCED_FACE('F138',(#763,#766),#752,.T.);
#768=CARTESIAN_POINT('',(1.75,-6.,1.5));
#769=DIRECTION('',(0.,0.,-1.));
#770=DIRECTION('',(-1.,0.,0.));
#771=AXIS2_PLACEMENT_3D('',#768,#769,#770);
#772=PLANE('',#771);
#773=ORIENTED_EDGE('',*,*,#154,.F.);
#774=DIRECTION('',(-1.,0.,0.));
#775=VECTOR('',#774,1.);
#776=CARTESIAN_POINT('',(3.75,-0.5,1.5));
#777=LINE('',#776,#775);
#778=EDGE_CURVE('E403',#313,#145,#777,.T.);
#779=ORIENTED_EDGE('',*,*,#778,.F.);
#780=ORIENTED_EDGE('',*,*,#316,.T.);
#781=ORIENTED_EDGE('',*,*,#718,.T.);
#782=EDGE_LOOP('',(#773,#779,#780,#781));
#783=FACE_BOUND('',#782,.T.);
#784=ADVANCED_FACE('F738',(#783),#772,.F.);
#785=CARTESIAN_POINT('',(-2.25,-6.,1.5));
#786=DIRECTION('',(0.,0.,-1.));
#787=DIRECTION('',(-1.,0.,0.));
#788=AXIS2_PLACEMENT_3D('',#785,#786,#787);
#789=PLANE('',#788);
#790=ORIENTED_EDGE('',*,*,#448,.F.);
#791=DIRECTION('',(1.,0.,0.));
#792=VECTOR('',#791,1.);
#793=CARTESIAN_POINT('',(-2.25,-0.5,1.5));
#794=LINE('',#793,#792);
#795=EDGE_CURVE('E588',#439,#603,#794,.T.);
#796=ORIENTED_EDGE('',*,*,#795,.T.);
#797=ORIENTED_EDGE('',*,*,#606,.T.);
#798=ORIENTED_EDGE('',*,*,#740,.T.);
#799=EDGE_LOOP('',(#790,#796,#797,#798));
#800=FACE_BOUND('',#799,.T.);
#801=ADVANCED_FACE('F735',(#800),#789,.F.);
#802=CARTESIAN_POINT('',(3.75,-4.5,0.));
#803=DIRECTION('',(-1.,0.,0.));
#804=DIRECTION('',(0.,0.,1.));
#805=AXIS2_PLACEMENT_3D('',#802,#803,#804);
#806=CYLINDRICAL_SURFACE('',#805,1.5);
#807=ORIENTED_EDGE('',*,*,#657,.T.);
#808=DIRECTION('',(-1.,0.,0.));
#809=VECTOR('',#808,1.);
#810=CARTESIAN_POINT('',(3.75,-5.92183021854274,0.477910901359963));
#811=LINE('',#810,#809);
#812=EDGE_CURVE('E400',#647,#514,#811,.T.);
#813=ORIENTED_EDGE('',*,*,#812,.T.);
#814=ORIENTED_EDGE('',*,*,#515,.F.);
#815=DIRECTION('',(-1.,0.,0.));
#816=VECTOR('',#815,1.);
#817=CARTESIAN_POINT('',(3.75,-5.92183021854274,-0.477910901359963));
#818=LINE('',#817,#816);
#819=EDGE_CURVE('E483',#656,#505,#818,.T.);
#820=ORIENTED_EDGE('',*,*,#819,.F.);
#821=EDGE_LOOP('',(#807,#813,#814,#820));
#822=FACE_BOUND('',#821,.T.);
#823=ADVANCED_FACE('F721',(#822),#806,.T.);
#824=CARTESIAN_POINT('',(3.75,-5.68485851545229,-0.398259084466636));
#825=DIRECTION('',(-1.,0.,0.));
#826=DIRECTION('',(0.,0.,1.));
#827=AXIS2_PLACEMENT_3D('',#824,#825,#826);
#828=CYLINDRICAL_SURFACE('',#827,0.25);
#829=ORIENTED_EDGE('',*,*,#819,.T.);
#830=ORIENTED_EDGE('',*,*,#506,.T.);
#831=DIRECTION('',(-1.,0.,0.));
#832=VECTOR('',#831,1.);
#833=CARTESIAN_POINT('',(3.75,-5.75410647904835,-0.638477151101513));
#834=LINE('',#833,#832);
#835=EDGE_CURVE('E498',#665,#496,#834,.T.);
#836=ORIENTED_EDGE('',*,*,#835,.F.);
#837=ORIENTED_EDGE('',*,*,#666,.F.);
#838=EDGE_LOOP('',(#829,#830,#836,#837));
#839=FACE_BOUND('',#838,.T.);
#840=ADVANCED_FACE('F717',(#839),#828,.T.);
#841=CARTESIAN_POINT('',(3.75,-10.5536374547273,0.745089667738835));
#842=DIRECTION('',(0.,-0.276991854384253,-0.960872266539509));
#843=DIRECTION('',(0.,0.960872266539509,-0.276991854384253));
#844=AXIS2_PLACEMENT_3D('',#841,#842,#843);
#845=PLANE('',#844);
#846=ORIENTED_EDGE('',*,*,#674,.T.);
#847=ORIENTED_EDGE('',*,*,#835,.T.);
#848=ORIENTED_EDGE('',*,*,#497,.F.);
#849=DIRECTION('',(-1.,0.,0.));
#850=VECTOR('',#849,1.);
#851=CARTESIAN_POINT('',(3.75,-4.53393308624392,-0.990218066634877));
#852=LINE('',#851,#850);
#853=EDGE_CURVE('E495',#673,#488,#852,.T.);
#854=ORIENTED_EDGE('',*,*,#853,.F.);
#855=EDGE_LOOP('',(#846,#847,#848,#854));
#856=FACE_BOUND('',#855,.T.);
#857=ADVANCED_FACE('F712',(#856),#845,.T.);
#858=CARTESIAN_POINT('',(3.75,-4.46468512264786,-0.75));
#859=DIRECTION('',(-1.,0.,0.));
#860=DIRECTION('',(0.,0.,1.));
#861=AXIS2_PLACEMENT_3D('',#858,#859,#860);
#862=CYLINDRICAL_SURFACE('',#861,0.25);
#863=ORIENTED_EDGE('',*,*,#853,.T.);
#864=ORIENTED_EDGE('',*,*,#489,.T.);
#865=DIRECTION('',(-1.,0.,0.));
#866=VECTOR('',#865,1.);
#867=CARTESIAN_POINT('',(3.75,-4.46468512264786,-1.));
#868=LINE('',#867,#866);
#869=EDGE_CURVE('E492',#682,#479,#868,.T.);
#870=ORIENTED_EDGE('',*,*,#869,.F.);
#871=ORIENTED_EDGE('',*,*,#683,.F.);
#872=EDGE_LOOP('',(#863,#864,#870,#871));
#873=FACE_BOUND('',#872,.T.);
#874=ADVANCED_FACE('F707',(#873),#862,.T.);
#875=CARTESIAN_POINT('',(3.75,-10.7684253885,-1.));
#876=DIRECTION('',(0.,0.,-1.));
#877=DIRECTION('',(-1.,0.,0.));
#878=AXIS2_PLACEMENT_3D('',#875,#876,#877);
#879=PLANE('',#878);
#880=ORIENTED_EDGE('',*,*,#691,.T.);
#881=ORIENTED_EDGE('',*,*,#869,.T.);
#882=ORIENTED_EDGE('',*,*,#480,.F.);
#883=DIRECTION('',(-1.,0.,0.));
#884=VECTOR('',#883,1.);
#885=CARTESIAN_POINT('',(3.75,-0.5,-1.));
#886=LINE('',#885,#884);
#887=EDGE_CURVE('E489',#690,#471,#886,.T.);
#888=ORIENTED_EDGE('',*,*,#887,.F.);
#889=EDGE_LOOP('',(#880,#881,#882,#888));
#890=FACE_BOUND('',#889,.T.);
#891=ADVANCED_FACE('F702',(#890),#879,.T.);
#892=CARTESIAN_POINT('',(3.75,-0.5,0.));
#893=DIRECTION('',(0.,-1.,0.));
#894=DIRECTION('',(0.,0.,-1.));
#895=AXIS2_PLACEMENT_3D('',#892,#893,#894);
#896=PLANE('',#895);
#897=ORIENTED_EDGE('',*,*,#697,.T.);
#898=ORIENTED_EDGE('',*,*,#887,.T.);
#899=ORIENTED_EDGE('',*,*,#472,.F.);
#900=ORIENTED_EDGE('',*,*,#562,.F.);
#901=EDGE_LOOP('',(#897,#898,#899,#900));
#902=FACE_BOUND('',#901,.T.);
#903=ADVANCED_FACE('F696',(#902),#896,.T.);
#904=ORIENTED_EDGE('',*,*,#178,.T.);
#905=ORIENTED_EDGE('',*,*,#272,.F.);
#906=ORIENTED_EDGE('',*,*,#407,.T.);
#907=EDGE_CURVE('E488',#400,#177,#886,.T.);
#908=ORIENTED_EDGE('',*,*,#907,.T.);
#909=EDGE_LOOP('',(#904,#905,#906,#908));
#910=FACE_BOUND('',#909,.T.);
#911=ADVANCED_FACE('F692',(#910),#896,.T.);
#912=ORIENTED_EDGE('',*,*,#186,.T.);
#913=ORIENTED_EDGE('',*,*,#907,.F.);
#914=ORIENTED_EDGE('',*,*,#401,.T.);
#915=EDGE_CURVE('E491',#392,#185,#868,.T.);
#916=ORIENTED_EDGE('',*,*,#915,.T.);
#917=EDGE_LOOP('',(#912,#913,#914,#916));
#918=FACE_BOUND('',#917,.T.);
#919=ADVANCED_FACE('F695',(#918),#879,.T.);
#920=ORIENTED_EDGE('',*,*,#915,.F.);
#921=ORIENTED_EDGE('',*,*,#393,.F.);
#922=EDGE_CURVE('E494',#383,#194,#852,.T.);
#923=ORIENTED_EDGE('',*,*,#922,.T.);
#924=ORIENTED_EDGE('',*,*,#195,.F.);
#925=EDGE_LOOP('',(#920,#921,#923,#924));
#926=FACE_BOUND('',#925,.T.);
#927=ADVANCED_FACE('F700',(#926),#862,.T.);
#928=ORIENTED_EDGE('',*,*,#203,.T.);
#929=ORIENTED_EDGE('',*,*,#922,.F.);
#930=ORIENTED_EDGE('',*,*,#384,.T.);
#931=EDGE_CURVE('E497',#375,#202,#834,.T.);
#932=ORIENTED_EDGE('',*,*,#931,.T.);
#933=EDGE_LOOP('',(#928,#929,#930,#932));
#934=FACE_BOUND('',#933,.T.);
#935=ADVANCED_FACE('F705',(#934),#845,.T.);
#936=ORIENTED_EDGE('',*,*,#931,.F.);
#937=ORIENTED_EDGE('',*,*,#376,.F.);
#938=EDGE_CURVE('E500',#366,#211,#818,.T.);
#939=ORIENTED_EDGE('',*,*,#938,.T.);
#940=ORIENTED_EDGE('',*,*,#212,.F.);
#941=EDGE_LOOP('',(#936,#937,#939,#940));
#942=FACE_BOUND('',#941,.T.);
#943=ADVANCED_FACE('F710',(#942),#828,.T.);
#944=ORIENTED_EDGE('',*,*,#221,.T.);
#945=ORIENTED_EDGE('',*,*,#938,.F.);
#946=ORIENTED_EDGE('',*,*,#367,.T.);
#947=EDGE_CURVE('E399',#357,#220,#811,.T.);
#948=ORIENTED_EDGE('',*,*,#947,.T.);
#949=EDGE_LOOP('',(#944,#945,#946,#948));
#950=FACE_BOUND('',#949,.T.);
#951=ADVANCED_FACE('F715',(#950),#806,.T.);
#952=CARTESIAN_POINT('',(3.75,-4.5,0.));
#953=DIRECTION('',(-1.,0.,0.));
#954=DIRECTION('',(0.,0.,1.));
#955=AXIS2_PLACEMENT_3D('',#952,#953,#954);
#956=CYLINDRICAL_SURFACE('',#955,0.75);
#957=ORIENTED_EDGE('',*,*,#550,.T.);
#958=EDGE_LOOP('',(#957));
#959=FACE_BOUND('',#958,.T.);
#960=ORIENTED_EDGE('',*,*,#594,.F.);
#961=EDGE_LOOP('',(#960));
#962=FACE_BOUND('',#961,.T.);
#963=ADVANCED_FACE('F690',(#959,#962),#956,.F.);
#964=ORIENTED_EDGE('',*,*,#304,.F.);
#965=EDGE_LOOP('',(#964));
#966=FACE_BOUND('',#965,.T.);
#967=ORIENTED_EDGE('',*,*,#256,.F.);
#968=EDGE_LOOP('',(#967));
#969=FACE_BOUND('',#968,.T.);
#970=ADVANCED_FACE('F673',(#966,#969),#956,.F.);
#971=CARTESIAN_POINT('',(3.75,-10.5536374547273,-0.745089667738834));
#972=DIRECTION('',(0.,0.276991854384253,-0.960872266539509));
#973=DIRECTION('',(0.,0.960872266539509,0.276991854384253));
#974=AXIS2_PLACEMENT_3D('',#971,#972,#973);
#975=PLANE('',#974);
#976=DIRECTION('',(-1.,0.,0.));
#977=VECTOR('',#976,1.);
#978=CARTESIAN_POINT('',(3.75,-5.75410647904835,0.638477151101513));
#979=LINE('',#978,#977);
#980=EDGE_CURVE('E398',#348,#229,#979,.T.);
#981=ORIENTED_EDGE('',*,*,#980,.F.);
#982=ORIENTED_EDGE('',*,*,#349,.F.);
#983=DIRECTION('',(-1.,0.,0.));
#984=VECTOR('',#983,1.);
#985=CARTESIAN_POINT('',(3.75,-4.53393308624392,0.990218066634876));
#986=LINE('',#985,#984);
#987=EDGE_CURVE('E395',#340,#237,#986,.T.);
#988=ORIENTED_EDGE('',*,*,#987,.T.);
#989=ORIENTED_EDGE('',*,*,#238,.F.);
#990=EDGE_LOOP('',(#981,#982,#988,#989));
#991=FACE_BOUND('',#990,.T.);
#992=ADVANCED_FACE('F669',(#991),#975,.F.);
#993=CARTESIAN_POINT('',(3.75,-5.68485851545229,0.398259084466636));
#994=DIRECTION('',(-1.,0.,0.));
#995=DIRECTION('',(0.,0.,1.));
#996=AXIS2_PLACEMENT_3D('',#993,#994,#995);
#997=CYLINDRICAL_SURFACE('',#996,0.25);
#998=ORIENTED_EDGE('',*,*,#947,.F.);
#999=ORIENTED_EDGE('',*,*,#358,.F.);
#1000=ORIENTED_EDGE('',*,*,#980,.T.);
#1001=ORIENTED_EDGE('',*,*,#230,.F.);
#1002=EDGE_LOOP('',(#998,#999,#1000,#1001));
#1003=FACE_BOUND('',#1002,.T.);
#1004=ADVANCED_FACE('F672',(#1003),#997,.T.);
#1005=CARTESIAN_POINT('',(3.75,-0.5,0.));
#1006=DIRECTION('',(0.,1.,0.));
#1007=DIRECTION('',(0.,0.,1.));
#1008=AXIS2_PLACEMENT_3D('',#1005,#1006,#1007);
#1009=PLANE('',#1008);
#1010=DIRECTION('',(-1.,0.,0.));
#1011=VECTOR('',#1010,1.);
#1012=CARTESIAN_POINT('',(3.75,-0.5,1.));
#1013=LINE('',#1012,#1011);
#1014=EDGE_CURVE('E405',#323,#137,#1013,.T.);
#1015=ORIENTED_EDGE('',*,*,#1014,.F.);
#1016=ORIENTED_EDGE('',*,*,#324,.F.);
#1017=ORIENTED_EDGE('',*,*,#778,.T.);
#1018=ORIENTED_EDGE('',*,*,#146,.F.);
#1019=EDGE_LOOP('',(#1015,#1016,#1017,#1018));
#1020=FACE_BOUND('',#1019,.T.);
#1021=ADVANCED_FACE('F678',(#1020),#1009,.F.);
#1022=CARTESIAN_POINT('',(3.75,-10.7684253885,1.));
#1023=DIRECTION('',(0.,0.,-1.));
#1024=DIRECTION('',(-1.,0.,0.));
#1025=AXIS2_PLACEMENT_3D('',#1022,#1023,#1024);
#1026=PLANE('',#1025);
#1027=DIRECTION('',(-1.,0.,0.));
#1028=VECTOR('',#1027,1.);
#1029=CARTESIAN_POINT('',(3.75,-4.46468512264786,1.));
#1030=LINE('',#1029,#1028);
#1031=EDGE_CURVE('E408',#331,#135,#1030,.T.);
#1032=ORIENTED_EDGE('',*,*,#1031,.F.);
#1033=ORIENTED_EDGE('',*,*,#332,.F.);
#1034=ORIENTED_EDGE('',*,*,#1014,.T.);
#1035=ORIENTED_EDGE('',*,*,#138,.F.);
#1036=EDGE_LOOP('',(#1032,#1033,#1034,#1035));
#1037=FACE_BOUND('',#1036,.T.);
#1038=ADVANCED_FACE('F667',(#1037),#1026,.F.);
#1039=CARTESIAN_POINT('',(3.75,-4.46468512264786,0.75));
#1040=DIRECTION('',(-1.,0.,0.));
#1041=DIRECTION('',(0.,0.,1.));
#1042=AXIS2_PLACEMENT_3D('',#1039,#1040,#1041);
#1043=CYLINDRICAL_SURFACE('',#1042,0.25);
#1044=ORIENTED_EDGE('',*,*,#245,.T.);
#1045=ORIENTED_EDGE('',*,*,#987,.F.);
#1046=ORIENTED_EDGE('',*,*,#341,.T.);
#1047=ORIENTED_EDGE('',*,*,#1031,.T.);
#1048=EDGE_LOOP('',(#1044,#1045,#1046,#1047));
#1049=FACE_BOUND('',#1048,.T.);
#1050=ADVANCED_FACE('F663',(#1049),#1043,.T.);
#1051=ORIENTED_EDGE('',*,*,#631,.T.);
#1052=EDGE_CURVE('E409',#621,#431,#1030,.T.);
#1053=ORIENTED_EDGE('',*,*,#1052,.T.);
#1054=ORIENTED_EDGE('',*,*,#539,.F.);
#1055=EDGE_CURVE('E393',#630,#531,#986,.T.);
#1056=ORIENTED_EDGE('',*,*,#1055,.F.);
#1057=EDGE_LOOP('',(#1051,#1053,#1054,#1056));
#1058=FACE_BOUND('',#1057,.T.);
#1059=ADVANCED_FACE('F666',(#1058),#1043,.T.);
#1060=EDGE_CURVE('E406',#613,#429,#1013,.T.);
#1061=ORIENTED_EDGE('',*,*,#1060,.T.);
#1062=ORIENTED_EDGE('',*,*,#432,.T.);
#1063=ORIENTED_EDGE('',*,*,#1052,.F.);
#1064=ORIENTED_EDGE('',*,*,#622,.F.);
#1065=EDGE_LOOP('',(#1061,#1062,#1063,#1064));
#1066=FACE_BOUND('',#1065,.T.);
#1067=ADVANCED_FACE('F687',(#1066),#1026,.F.);
#1068=EDGE_CURVE('E396',#638,#523,#979,.T.);
#1069=ORIENTED_EDGE('',*,*,#1068,.T.);
#1070=ORIENTED_EDGE('',*,*,#524,.T.);
#1071=ORIENTED_EDGE('',*,*,#812,.F.);
#1072=ORIENTED_EDGE('',*,*,#648,.F.);
#1073=EDGE_LOOP('',(#1069,#1070,#1071,#1072));
#1074=FACE_BOUND('',#1073,.T.);
#1075=ADVANCED_FACE('F680',(#1074),#997,.T.);
#1076=ORIENTED_EDGE('',*,*,#1055,.T.);
#1077=ORIENTED_EDGE('',*,*,#532,.T.);
#1078=ORIENTED_EDGE('',*,*,#1068,.F.);
#1079=ORIENTED_EDGE('',*,*,#639,.F.);
#1080=EDGE_LOOP('',(#1076,#1077,#1078,#1079));
#1081=FACE_BOUND('',#1080,.T.);
#1082=ADVANCED_FACE('F675',(#1081),#975,.F.);
#1083=ORIENTED_EDGE('',*,*,#795,.F.);
#1084=ORIENTED_EDGE('',*,*,#440,.T.);
#1085=ORIENTED_EDGE('',*,*,#1060,.F.);
#1086=ORIENTED_EDGE('',*,*,#614,.F.);
#1087=EDGE_LOOP('',(#1083,#1084,#1085,#1086));
#1088=FACE_BOUND('',#1087,.T.);
#1089=ADVANCED_FACE('F657',(#1088),#1009,.F.);
#1090=CARTESIAN_POINT('',(0.,6.,0.));
#1091=DIRECTION('',(0.,1.,0.));
#1092=DIRECTION('',(0.,0.,1.));
#1093=AXIS2_PLACEMENT_3D('',#1090,#1091,#1092);
#1094=PLANE('',#1093);
#1095=CARTESIAN_POINT('',(0.,6.,0.));
#1096=DIRECTION('',(0.,1.,0.));
#1097=DIRECTION('',(0.,0.,1.));
#1098=AXIS2_PLACEMENT_3D('',#1095,#1096,#1097);
#1099=CIRCLE('',#1098,4.5);
#1100=CARTESIAN_POINT('',(0.,6.,4.5));
#1101=VERTEX_POINT('',#1100);
#1102=EDGE_CURVE('E607',#1101,#1101,#1099,.F.);
#1103=ORIENTED_EDGE('',*,*,#1102,.T.);
#1104=EDGE_LOOP('',(#1103));
#1105=FACE_BOUND('',#1104,.T.);
#1106=ORIENTED_EDGE('',*,*,#760,.T.);
#1107=EDGE_LOOP('',(#1106));
#1108=FACE_BOUND('',#1107,.T.);
#1109=ADVANCED_FACE('F655',(#1105,#1108),#1094,.F.);
#1110=CARTESIAN_POINT('',(0.,8.,0.));
#1111=DIRECTION('',(0.,-1.,0.));
#1112=DIRECTION('',(0.,0.,-1.));
#1113=AXIS2_PLACEMENT_3D('',#1110,#1111,#1112);
#1114=CYLINDRICAL_SURFACE('',#1113,5.);
#1115=CARTESIAN_POINT('',(0.,6.5,0.));
#1116=DIRECTION('',(0.,1.,0.));
#1117=DIRECTION('',(0.,0.,1.));
#1118=AXIS2_PLACEMENT_3D('',#1115,#1116,#1117);
#1119=CIRCLE('',#1118,5.);
#1120=CARTESIAN_POINT('',(0.,6.5,5.));
#1121=VERTEX_POINT('',#1120);
#1122=EDGE_CURVE('E604',#1121,#1121,#1119,.T.);
#1123=ORIENTED_EDGE('',*,*,#1122,.T.);
#1124=EDGE_LOOP('',(#1123));
#1125=FACE_BOUND('',#1124,.T.);
#1126=ORIENTED_EDGE('',*,*,#84,.F.);
#1127=EDGE_LOOP('',(#1126));
#1128=FACE_BOUND('',#1127,.T.);
#1129=ADVANCED_FACE('F653',(#1125,#1128),#1114,.T.);
#1130=CARTESIAN_POINT('',(0.,6.5,0.));
#1131=DIRECTION('',(0.,1.,0.));
#1132=DIRECTION('',(0.,0.,1.));
#1133=AXIS2_PLACEMENT_3D('',#1130,#1131,#1132);
#1134=TOROIDAL_SURFACE('',#1133,4.5,0.5);
#1135=ORIENTED_EDGE('',*,*,#1102,.F.);
#1136=EDGE_LOOP('',(#1135));
#1137=FACE_BOUND('',#1136,.T.);
#1138=ORIENTED_EDGE('',*,*,#1122,.F.);
#1139=EDGE_LOOP('',(#1138));
#1140=FACE_BOUND('',#1139,.T.);
#1141=ADVANCED_FACE('F650',(#1137,#1140),#1134,.T.);
#1142=CARTESIAN_POINT('',(0.,15.,0.));
#1143=DIRECTION('',(0.,-1.,0.));
#1144=DIRECTION('',(0.,0.,-1.));
#1145=AXIS2_PLACEMENT_3D('',#1142,#1143,#1144);
#1146=CYLINDRICAL_SURFACE('',#1145,3.5);
#1147=ORIENTED_EDGE('',*,*,#105,.T.);
#1148=DIRECTION('',(0.,-1.,0.));
#1149=VECTOR('',#1148,1.);
#1150=CARTESIAN_POINT('',(-3.,15.,-1.802775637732));
#1151=LINE('',#1150,#1149);
#1152=EDGE_CURVE('E347',#32,#93,#1151,.T.);
#1153=ORIENTED_EDGE('',*,*,#1152,.F.);
#1154=ORIENTED_EDGE('',*,*,#33,.F.);
#1155=DIRECTION('',(0.,-1.,0.));
#1156=VECTOR('',#1155,1.);
#1157=CARTESIAN_POINT('',(3.,15.,-1.802775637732));
#1158=LINE('',#1157,#1156);
#1159=EDGE_CURVE('E366',#30,#104,#1158,.T.);
#1160=ORIENTED_EDGE('',*,*,#1159,.T.);
#1161=EDGE_LOOP('',(#1147,#1153,#1154,#1160));
#1162=FACE_BOUND('',#1161,.T.);
#1163=ADVANCED_FACE('F364',(#1162),#1146,.T.);
#1164=CARTESIAN_POINT('',(-3.,15.,1.802775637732));
#1165=DIRECTION('',(1.,0.,0.));
#1166=DIRECTION('',(0.,0.,-1.));
#1167=AXIS2_PLACEMENT_3D('',#1164,#1165,#1166);
#1168=PLANE('',#1167);
#1169=ORIENTED_EDGE('',*,*,#96,.T.);
#1170=DIRECTION('',(0.,-1.,0.));
#1171=VECTOR('',#1170,1.);
#1172=CARTESIAN_POINT('',(-3.,15.,1.802775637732));
#1173=LINE('',#1172,#1171);
#1174=EDGE_CURVE('E359',#40,#95,#1173,.T.);
#1175=ORIENTED_EDGE('',*,*,#1174,.F.);
#1176=ORIENTED_EDGE('',*,*,#41,.F.);
#1177=ORIENTED_EDGE('',*,*,#1152,.T.);
#1178=EDGE_LOOP('',(#1169,#1175,#1176,#1177));
#1179=FACE_BOUND('',#1178,.T.);
#1180=ADVANCED_FACE('F349',(#1179),#1168,.F.);
#1181=CARTESIAN_POINT('',(0.,15.,0.));
#1182=DIRECTION('',(0.,-1.,0.));
#1183=DIRECTION('',(0.,0.,-1.));
#1184=AXIS2_PLACEMENT_3D('',#1181,#1182,#1183);
#1185=CYLINDRICAL_SURFACE('',#1184,3.5);
#1186=ORIENTED_EDGE('',*,*,#120,.T.);
#1187=DIRECTION('',(0.,-1.,0.));
#1188=VECTOR('',#1187,1.);
#1189=CARTESIAN_POINT('',(3.,15.,1.80277563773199));
#1190=LINE('',#1189,#1188);
#1191=EDGE_CURVE('E151',#49,#112,#1190,.T.);
#1192=ORIENTED_EDGE('',*,*,#1191,.F.);
#1193=ORIENTED_EDGE('',*,*,#50,.F.);
#1194=ORIENTED_EDGE('',*,*,#1174,.T.);
#1195=EDGE_LOOP('',(#1186,#1192,#1193,#1194));
#1196=FACE_BOUND('',#1195,.T.);
#1197=ADVANCED_FACE('F642',(#1196),#1185,.T.);
#1198=CARTESIAN_POINT('',(3.,15.,1.802775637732));
#1199=DIRECTION('',(-1.,0.,0.));
#1200=DIRECTION('',(0.,0.,1.));
#1201=AXIS2_PLACEMENT_3D('',#1198,#1199,#1200);
#1202=PLANE('',#1201);
#1203=ORIENTED_EDGE('',*,*,#113,.T.);
#1204=ORIENTED_EDGE('',*,*,#1159,.F.);
#1205=ORIENTED_EDGE('',*,*,#56,.F.);
#1206=ORIENTED_EDGE('',*,*,#1191,.T.);
#1207=EDGE_LOOP('',(#1203,#1204,#1205,#1206));
#1208=FACE_BOUND('',#1207,.T.);
#1209=ADVANCED_FACE('F639',(#1208),#1202,.F.);
#1210=CARTESIAN_POINT('',(0.,18.,0.));
#1211=DIRECTION('',(0.,-1.,0.));
#1212=DIRECTION('',(0.,0.,-1.));
#1213=AXIS2_PLACEMENT_3D('',#1210,#1211,#1212);
#1214=CYLINDRICAL_SURFACE('',#1213,2.);
#1215=CARTESIAN_POINT('',(0.,18.,0.));
#1216=DIRECTION('',(0.,1.,0.));
#1217=DIRECTION('',(0.,0.,1.));
#1218=AXIS2_PLACEMENT_3D('',#1215,#1216,#1217);
#1219=CIRCLE('',#1218,2.);
#1220=CARTESIAN_POINT('',(0.,18.,2.));
#1221=VERTEX_POINT('',#1220);
#1222=EDGE_CURVE('E369',#1221,#1221,#1219,.T.);
#1223=ORIENTED_EDGE('',*,*,#1222,.F.);
#1224=EDGE_LOOP('',(#1223));
#1225=FACE_BOUND('',#1224,.T.);
#1226=ORIENTED_EDGE('',*,*,#67,.T.);
#1227=EDGE_LOOP('',(#1226));
#1228=FACE_BOUND('',#1227,.T.);
#1229=ADVANCED_FACE('F637',(#1225,#1228),#1214,.T.);
#1230=CARTESIAN_POINT('',(0.,18.,0.));
#1231=DIRECTION('',(0.,1.,0.));
#1232=DIRECTION('',(0.,0.,1.));
#1233=AXIS2_PLACEMENT_3D('',#1230,#1231,#1232);
#1234=PLANE('',#1233);
#1235=CARTESIAN_POINT('',(0.,18.,0.));
#1236=DIRECTION('',(0.,1.,0.));
#1237=DIRECTION('',(0.,0.,1.));
#1238=AXIS2_PLACEMENT_3D('',#1235,#1236,#1237);
#1239=CIRCLE('',#1238,3.);
#1240=CARTESIAN_POINT('',(0.,18.,3.));
#1241=VERTEX_POINT('',#1240);
#1242=EDGE_CURVE('E1043',#1241,#1241,#1239,.T.);
#1243=ORIENTED_EDGE('',*,*,#1242,.F.);
#1244=EDGE_LOOP('',(#1243));
#1245=FACE_BOUND('',#1244,.T.);
#1246=ORIENTED_EDGE('',*,*,#1222,.T.);
#1247=EDGE_LOOP('',(#1246));
#1248=FACE_BOUND('',#1247,.T.);
#1249=ADVANCED_FACE('F1010',(#1245,#1248),#1234,.F.);
#1250=CARTESIAN_POINT('',(0.,21.,0.));
#1251=DIRECTION('',(0.,-1.,0.));
#1252=DIRECTION('',(0.,0.,-1.));
#1253=AXIS2_PLACEMENT_3D('',#1250,#1251,#1252);
#1254=CYLINDRICAL_SURFACE('',#1253,3.);
#1255=CARTESIAN_POINT('',(0.,20.5,0.));
#1256=DIRECTION('',(0.,1.,0.));
#1257=DIRECTION('',(0.,0.,1.));
#1258=AXIS2_PLACEMENT_3D('',#1255,#1256,#1257);
#1259=CIRCLE('',#1258,3.);
#1260=CARTESIAN_POINT('',(0.,20.5,3.));
#1261=VERTEX_POINT('',#1260);
#1262=EDGE_CURVE('E12',#1261,#1261,#1259,.F.);
#1263=ORIENTED_EDGE('',*,*,#1262,.T.);
#1264=EDGE_LOOP('',(#1263));
#1265=FACE_BOUND('',#1264,.T.);
#1266=ORIENTED_EDGE('',*,*,#1242,.T.);
#1267=EDGE_LOOP('',(#1266));
#1268=FACE_BOUND('',#1267,.T.);
#1269=ADVANCED_FACE('F621',(#1265,#1268),#1254,.T.);
#1270=CARTESIAN_POINT('',(0.,21.,0.));
#1271=DIRECTION('',(0.,1.,0.));
#1272=DIRECTION('',(0.,0.,1.));
#1273=AXIS2_PLACEMENT_3D('',#1270,#1271,#1272);
#1274=PLANE('',#1273);
#1275=CARTESIAN_POINT('',(0.,21.,0.));
#1276=DIRECTION('',(0.,1.,0.));
#1277=DIRECTION('',(0.,0.,1.));
#1278=AXIS2_PLACEMENT_3D('',#1275,#1276,#1277);
#1279=CIRCLE('',#1278,2.5);
#1280=CARTESIAN_POINT('',(0.,21.,2.5));
#1281=VERTEX_POINT('',#1280);
#1282=EDGE_CURVE('E144',#1281,#1281,#1279,.T.);
#1283=ORIENTED_EDGE('',*,*,#1282,.T.);
#1284=EDGE_LOOP('',(#1283));
#1285=FACE_BOUND('',#1284,.T.);
#1286=ADVANCED_FACE('F612',(#1285),#1274,.T.);
#1287=CARTESIAN_POINT('',(0.,20.5,0.));
#1288=DIRECTION('',(0.,1.,0.));
#1289=DIRECTION('',(0.,0.,1.));
#1290=AXIS2_PLACEMENT_3D('',#1287,#1288,#1289);
#1291=TOROIDAL_SURFACE('',#1290,2.5,0.5);
#1292=ORIENTED_EDGE('',*,*,#1262,.F.);
#1293=EDGE_LOOP('',(#1292));
#1294=FACE_BOUND('',#1293,.T.);
#1295=ORIENTED_EDGE('',*,*,#1282,.F.);
#1296=EDGE_LOOP('',(#1295));
#1297=FACE_BOUND('',#1296,.T.);
#1298=ADVANCED_FACE('F614',(#1294,#1297),#1291,.T.);
#1299=CLOSED_SHELL('',(#71,#124,#260,#291,#418,#554,#581,#708,#747,#767,#784,#801,#823,#840,
#857,#874,#891,#903,#911,#919,#927,#935,#943,#951,#963,#970,#992,#1004,#1021,#1038,#1050,#1059,
#1067,#1075,#1082,#1089,#1109,#1129,#1141,#1163,#1180,#1197,#1209,#1229,#1249,#1269,#1286,#1298));
#1300=MANIFOLD_SOLID_BREP('B2',#1299);
#1301=ADVANCED_BREP_SHAPE_REPRESENTATION('',(#18,#1300),#14);
#1302=SHAPE_DEFINITION_REPRESENTATION(#9,#1301);
ENDSEC;
END-ISO-10303-21;
